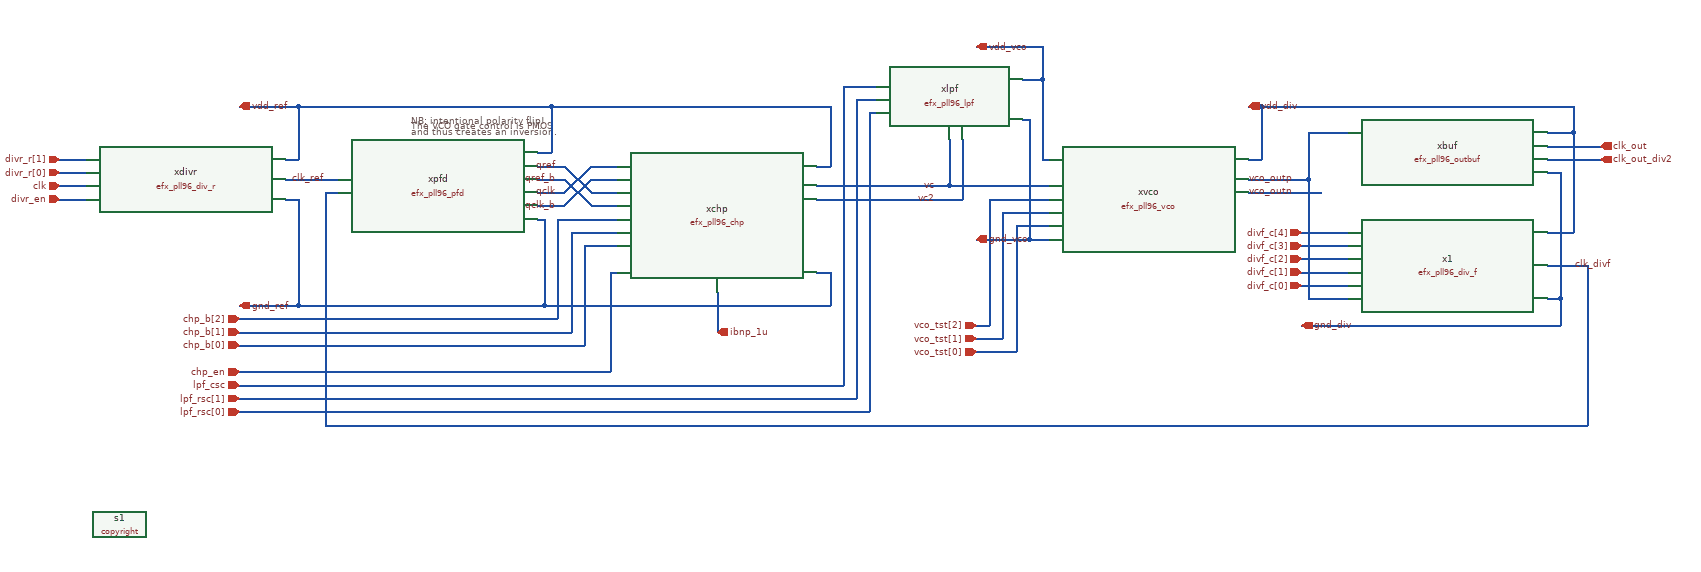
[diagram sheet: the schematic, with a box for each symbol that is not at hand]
v {xschem version=3.4.7 file_version=1.2}
G {}
K {}
V {}
S {}
E {}
T {NB: intentional polarity flip!
The VCO gate control is PMOS 
and thus creates an inversion.} 440 -610 0 0 0.2 0.2 {}
N 1050 -530 1070 -530 {
lab=vdd_ref}
N 1390 -540 1400 -540 {
lab=vdd_vco}
N 2150 -430 2190 -430 {
lab=vdd_div}
N 1700 -620 1720 -620 {
lab=vdd_div}
N 1050 -370 1070 -370 {
lab=gnd_ref}
N 630 -530 670 -530 {
lab=qref}
N 630 -510 670 -510 {
lab=qref_b}
N 630 -490 670 -490 {
lab=qclk}
N 630 -470 670 -470 {
lab=qclk_b}
N 710 -530 750 -530 {
lab=qclk}
N 710 -510 750 -510 {
lab=qclk_b}
N 710 -490 750 -490 {
lab=qref}
N 710 -470 750 -470 {
lab=qref_b}
N 670 -530 710 -490 {
lab=qref}
N 670 -510 710 -470 {
lab=qref_b}
N 670 -490 710 -530 {
lab=qclk}
N 670 -470 710 -510 {
lab=qclk_b}
N 1070 -620 1070 -530 {
lab=vdd_ref}
N 630 -450 640 -450 {
lab=gnd_ref}
N 310 -490 330 -490 {
lab=clk_divf}
N -90 -500 -50 -500 {
lab=clk}
N 1700 -540 1720 -540 {
lab=vdd_div}
N 1720 -620 1720 -540 {
lab=vdd_div}
N 1700 -490 1770 -490 {
lab=vco_outn}
N 1790 -510 1790 -330 {
lab=vco_outp}
N 1700 -510 1790 -510 {
lab=vco_outp}
N 2150 -380 2210 -380 {
lab=clk_divf}
N 1780 -410 1850 -410 {
lab=divf_c[3]}
N 1780 -390 1850 -390 {
lab=divf_c[2]}
N 1780 -370 1850 -370 {
lab=divf_c[1]}
N 630 -550 650 -550 {
lab=vdd_ref}
N 2150 -580 2190 -580 {
lab=vdd_div}
N 2190 -580 2190 -430 {
lab=vdd_div}
N 1720 -620 2190 -620 {
lab=vdd_div}
N 2150 -520 2170 -520 {
lab=gnd_div}
N 2190 -620 2190 -580 {
lab=vdd_div}
N 2150 -560 2230 -560 {
lab=clk_out}
N 2150 -540 2230 -540 {
lab=clk_out_div2}
N 1790 -580 1790 -510 {
lab=vco_outp}
N 1790 -580 1850 -580 {
lab=vco_outp}
N 1250 -570 1250 -500 {
lab=vc}
N 1250 -500 1400 -500 {
lab=vc}
N 650 -620 1070 -620 {
lab=vdd_ref}
N 310 -490 310 -140 {
lab=clk_divf}
N 650 -620 650 -550 {
lab=vdd_ref}
N 1390 -660 1390 -540 {
lab=vdd_vco}
N 1360 -600 1370 -600 {
lab=gnd_vco}
N 1370 -420 1400 -420 {
lab=gnd_vco}
N 1370 -600 1370 -420 {
lab=gnd_vco}
N 1360 -660 1390 -660 {
lab=vdd_vco}
N 1390 -710 1390 -660 {
lab=vdd_vco}
N 270 -620 650 -620 {
lab=vdd_ref}
N 250 -540 270 -540 {
lab=vdd_ref}
N 270 -620 270 -540 {
lab=vdd_ref}
N 250 -480 270 -480 {
lab=gnd_ref}
N 1070 -370 1070 -320 {
lab=gnd_ref}
N 180 -620 270 -620 {
lab=vdd_ref}
N 250 -510 330 -510 {
lab=clk_ref}
N -90 -540 -50 -540 {
lab=divr_r[1]}
N -90 -480 -50 -480 {
lab=divr_en}
N 680 -430 750 -430 {
lab=chp_b[1]}
N 1110 -630 1110 -180 {
lab=lpf_rsc[1]}
N 640 -450 640 -320 {
lab=gnd_ref}
N 640 -320 1070 -320 {
lab=gnd_ref}
N 180 -220 740 -220 {
lab=chp_en}
N 700 -410 750 -410 {
lab=chp_b[0]}
N 700 -410 700 -260 {
lab=chp_b[0]}
N 180 -260 700 -260 {
lab=chp_b[0]}
N 180 -280 680 -280 {
lab=chp_b[1]}
N 1350 -440 1400 -440 {
lab=vco_tst[0]}
N 1350 -440 1350 -250 {
lab=vco_tst[0]}
N 1290 -250 1350 -250 {
lab=vco_tst[0]}
N 1290 -420 1370 -420 {
lab=gnd_vco}
N 1290 -710 1390 -710 {
lab=vdd_vco}
N 1110 -630 1140 -630 {
lab=lpf_rsc[1]}
N 180 -180 1110 -180 {
lab=lpf_rsc[1]}
N 1130 -610 1140 -610 {
lab=lpf_rsc[0]}
N 1130 -610 1130 -160 {
lab=lpf_rsc[0]}
N 180 -160 1130 -160 {
lab=lpf_rsc[0]}
N 1330 -460 1400 -460 {
lab=vco_tst[1]}
N 1330 -460 1330 -270 {
lab=vco_tst[1]}
N 1290 -270 1330 -270 {
lab=vco_tst[1]}
N 1290 -290 1310 -290 {
lab=vco_tst[2]}
N 1310 -480 1310 -290 {
lab=vco_tst[2]}
N 1310 -480 1400 -480 {
lab=vco_tst[2]}
N 1090 -650 1140 -650 {
lab=lpf_csc}
N 1090 -650 1090 -200 {
lab=lpf_csc}
N 180 -200 1090 -200 {
lab=lpf_csc}
N 310 -140 2210 -140 {
lab=clk_divf}
N -90 -520 -50 -520 {
lab=divr_r[0]}
N 1050 -500 1250 -500 {
lab=vc}
N 270 -320 640 -320 {
lab=gnd_ref}
N 180 -320 270 -320 {
lab=gnd_ref}
N 270 -480 270 -320 {
lab=gnd_ref}
N 900 -340 900 -280 {
lab=ibnp_1u}
N 660 -450 750 -450 {
lab=chp_b[2]}
N 660 -450 660 -300 {
lab=chp_b[2]}
N 180 -300 660 -300 {
lab=chp_b[2]}
N 680 -430 680 -280 {
lab=chp_b[1]}
N 740 -370 750 -370 {
lab=chp_en}
N 740 -370 740 -220 {
lab=chp_en}
N 2210 -380 2210 -140 {lab=clk_divf}
N 2150 -330 2170 -330 {lab=gnd_div}
N 1790 -330 1850 -330 {lab=vco_outp}
N 2170 -520 2170 -330 {
lab=gnd_div}
N 1780 -350 1850 -350 {
lab=divf_c[0]}
N 1780 -430 1850 -430 {lab=divf_c[4]}
N 2170 -330 2170 -290 {lab=gnd_div}
N 1780 -290 2170 -290 {
lab=gnd_div}
N 1050 -480 1270 -480 {lab=vc2}
N 1270 -570 1270 -480 {lab=vc2}
N 1770 -490 1810 -490 {lab=vco_outn}
C {title_efx.sym} 200 -40 0 0 {name=l1 author="ejfogleman"}
C {efx_pll96_lpf.sym} 1250 -630 0 0 {name=xlpf}
C {efx_pll96_pfd.sym} 480 -500 0 0 {name=xpfd}
C {efx_pll96_chp.sym} 900 -500 0 0 {name=xchp}
C {efx_pll96_vco.sym} 1550 -500 0 0 {name=xvco}
C {iopin.sym} 180 -620 0 1 {name=p1 lab=vdd_ref}
C {iopin.sym} 1290 -710 0 1 {name=p2 lab=vdd_vco}
C {iopin.sym} 1700 -620 0 1 {name=p3 lab=vdd_div}
C {iopin.sym} 180 -320 0 1 {name=p4 lab=gnd_ref}
C {iopin.sym} 900 -280 0 1 {name=p5 lab=ibnp_1u}
C {ipin.sym} -90 -500 0 0 {name=p6 lab=clk}
C {lab_wire.sym} 1770 -510 0 0 {name=p8 sig_type=std_logic lab=vco_outp
}
C {lab_wire.sym} 1770 -490 0 0 {name=p9 sig_type=std_logic lab=vco_outn}
C {ipin.sym} 1780 -430 0 0 {name=p10 lab=divf_c[4]}
C {ipin.sym} 1780 -410 0 0 {name=p11 lab=divf_c[3]}
C {ipin.sym} 1780 -390 0 0 {name=p12 lab=divf_c[2]}
C {ipin.sym} 1780 -370 0 0 {name=p13 lab=divf_c[1]}
C {ipin.sym} 1780 -350 0 0 {name=p14 lab=divf_c[0]}
C {lab_wire.sym} 1230 -500 0 0 {name=p23 sig_type=std_logic lab=vc}
C {lab_wire.sym} 660 -530 0 0 {name=p24 sig_type=std_logic lab=qref}
C {lab_wire.sym} 660 -510 0 0 {name=p25 sig_type=std_logic lab=qref_b}
C {lab_wire.sym} 660 -490 0 0 {name=p26 sig_type=std_logic lab=qclk}
C {lab_wire.sym} 660 -470 0 0 {name=p27 sig_type=std_logic lab=qclk_b}
C {efx_pll96_outbuf.sym} 2000 -550 0 0 {name=xbuf}
C {lab_wire.sym} 2190 -380 0 1 {name=p7 sig_type=std_logic lab=clk_divf
}
C {opin.sym} 2230 -560 0 0 {name=p28 lab=clk_out}
C {opin.sym} 2230 -540 0 0 {name=p29 lab=clk_out_div2}
C {iopin.sym} 1290 -420 0 1 {name=p32 lab=gnd_vco}
C {iopin.sym} 1780 -290 0 1 {name=p33 lab=gnd_div}
C {efx_pll96_div_r.sym} 100 -510 0 0 {name=xdivr}
C {lab_wire.sym} 310 -510 0 0 {name=p34 sig_type=std_logic lab=clk_ref}
C {ipin.sym} -90 -540 0 0 {name=p35 lab=divr_r[1]}
C {ipin.sym} -90 -480 0 0 {name=p37 lab=divr_en}
C {ipin.sym} 180 -200 0 0 {name=p39 lab=lpf_csc}
C {ipin.sym} 180 -280 0 0 {name=p40 lab=chp_b[1]}
C {ipin.sym} 180 -220 0 0 {name=p30 lab=chp_en}
C {ipin.sym} 1290 -250 0 0 {name=p43 lab=vco_tst[0]}
C {ipin.sym} 180 -160 0 0 {name=p41 lab=lpf_rsc[0]}
C {ipin.sym} 1290 -270 0 0 {name=p36 lab=vco_tst[1]}
C {ipin.sym} 1290 -290 0 0 {name=p38 lab=vco_tst[2]}
C {ipin.sym} 180 -180 0 0 {name=p42 lab=lpf_rsc[1]}
C {ipin.sym} -90 -520 0 0 {name=p44 lab=divr_r[0]}
C {ipin.sym} 180 -300 0 0 {name=p45 lab=chp_b[2]}
C {ipin.sym} 180 -260 0 0 {name=p46 lab=chp_b[0]}
C {copyright.sym} 0 10 0 0 {name=s1 place=header value="* Copyright (c) Eric Fogleman 2025 
* SPDX-License-Identifier: Apache-2.0"}
C {efx_pll96_div_f.sym} 2000 -380 0 0 {name=x1}
C {lab_wire.sym} 1230 -480 0 0 {name=p15 sig_type=std_logic lab=vc2}
C {noconn.sym} 1810 -490 0 1 {name=l2}
